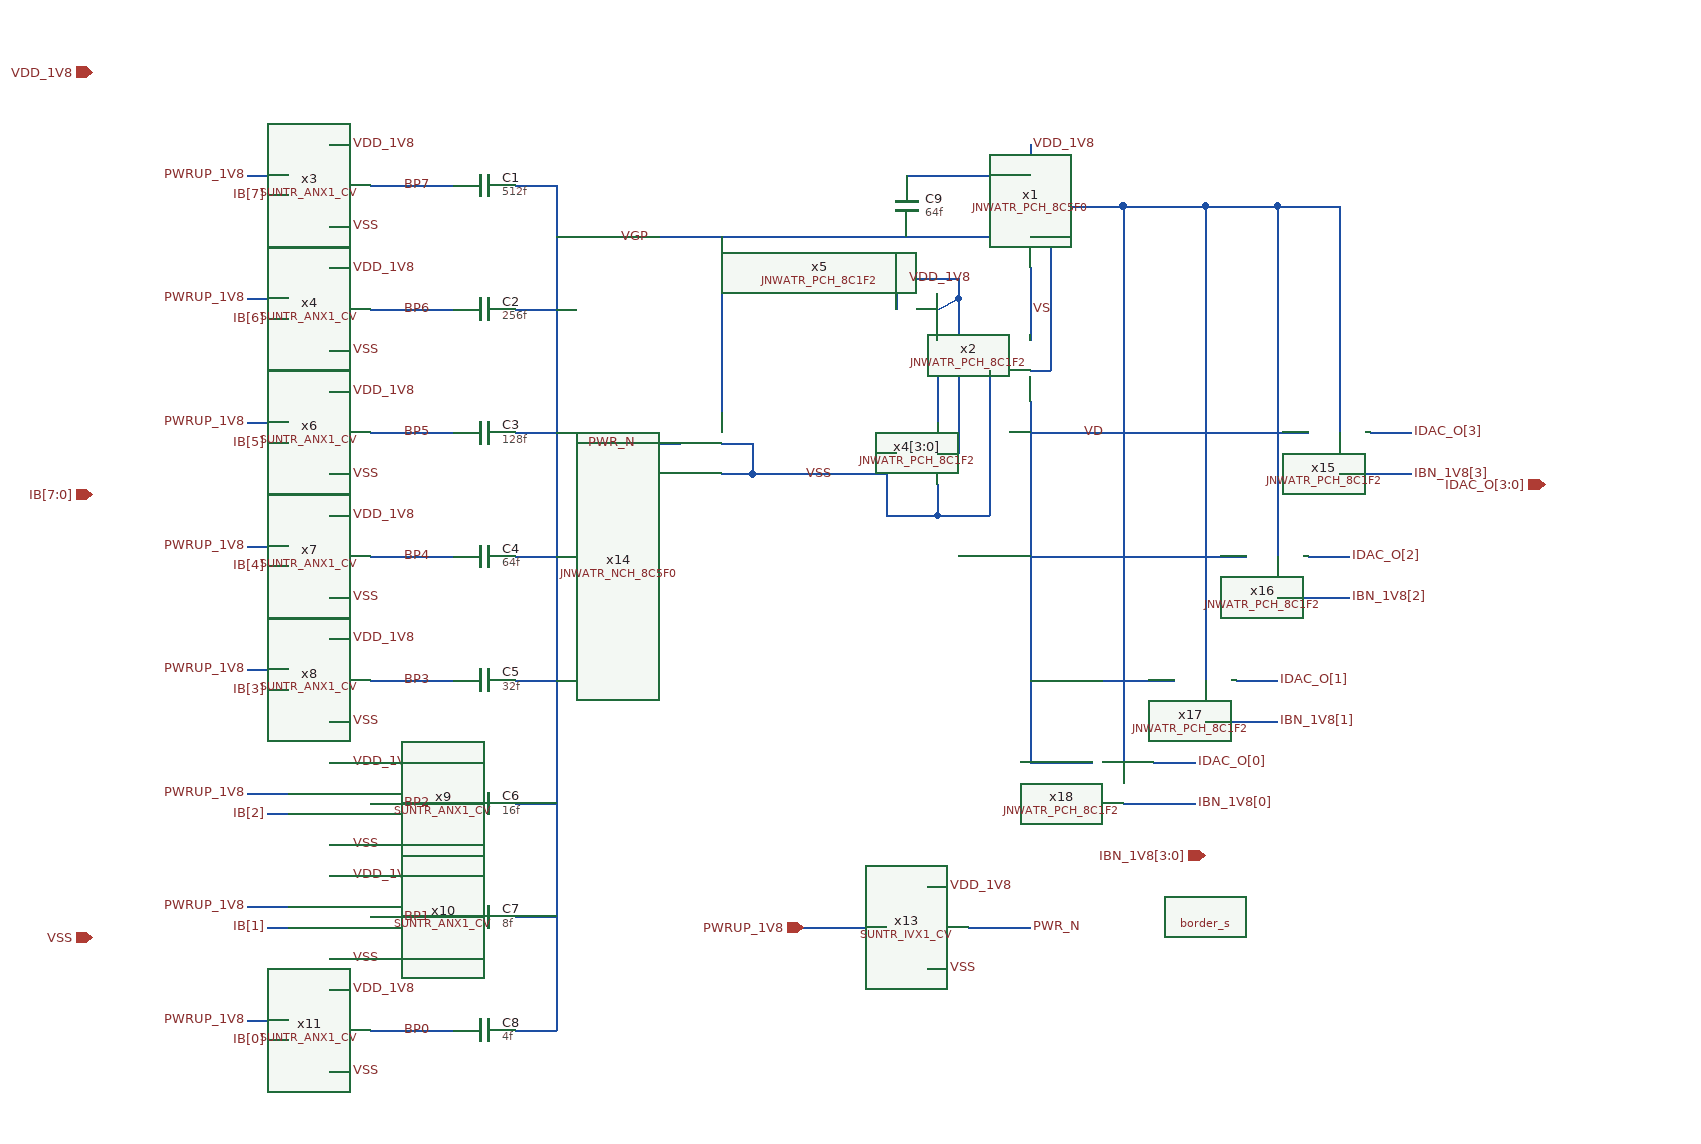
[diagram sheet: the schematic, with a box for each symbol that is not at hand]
v {xschem version=3.4.5 file_version=1.2
}
G {}
K {}
V {}
S {}
E {}
N 1080 -800 1080 -730 {
lab=VS}
N 1080 -700 1100 -700 {
lab=VDD_1V8}
N 1100 -830 1100 -700 {
lab=VDD_1V8}
N 1080 -830 1100 -830 {
lab=VDD_1V8}
N 1100 -860 1100 -830 {
lab=VDD_1V8}
N 1080 -860 1100 -860 {
lab=VDD_1V8}
N 1080 -920 1080 -860 {
lab=VDD_1V8}
N 990 -700 990 -650 {
lab=#net1}
N 990 -730 990 -700 {
lab=#net1}
N 990 -760 1010 -770 {
lab=VDD_1V8}
N 1010 -790 1010 -770 {
lab=VDD_1V8}
N 990 -790 1010 -790 {
lab=VDD_1V8}
N 950 -790 950 -760 {
lab=VDD_1V8}
N 950 -790 990 -790 {
lab=VDD_1V8}
N 990 -620 1010 -620 {
lab=VDD_1V8}
N 1010 -770 1010 -620 {
lab=VDD_1V8}
N 990 -590 990 -560 {
lab=VSS}
N 940 -560 990 -560 {
lab=VSS}
N 940 -620 940 -560 {
lab=VSS}
N 940 -620 950 -620 {
lab=VSS}
N 710 -830 1040 -830 {
lab=VGP}
N 400 -920 420 -920 {
lab=VDD_1V8}
N 400 -840 420 -840 {
lab=VSS}
N 340 -870 360 -870 {
lab=IB[7]}
N 400 -800 420 -800 {
lab=VDD_1V8}
N 400 -720 420 -720 {
lab=VSS}
N 340 -750 360 -750 {
lab=IB[6]}
N 400 -680 420 -680 {
lab=VDD_1V8}
N 400 -600 420 -600 {
lab=VSS}
N 340 -630 360 -630 {
lab=IB[5]}
N 400 -560 420 -560 {
lab=VDD_1V8}
N 400 -480 420 -480 {
lab=VSS}
N 340 -510 360 -510 {
lab=IB[4]}
N 400 -440 420 -440 {
lab=VDD_1V8}
N 400 -360 420 -360 {
lab=VSS}
N 340 -390 360 -390 {
lab=IB[3]}
N 400 -240 420 -240 {
lab=VSS}
N 340 -270 360 -270 {
lab=IB[2]}
N 400 -210 420 -210 {
lab=VDD_1V8}
N 400 -130 420 -130 {
lab=VSS}
N 340 -160 360 -160 {
lab=IB[1]}
N 400 -100 420 -100 {
lab=VDD_1V8}
N 400 -20 420 -20 {
lab=VSS}
N 340 -50 360 -50 {
lab=IB[0]}
N 440 -880 520 -880 {
lab=BP7}
N 580 -880 620 -880 {
lab=VGP}
N 440 -760 520 -760 {
lab=BP6}
N 580 -760 620 -760 {
lab=VGP}
N 440 -640 520 -640 {
lab=BP5}
N 580 -640 620 -640 {
lab=VGP}
N 440 -520 520 -520 {
lab=BP4}
N 580 -520 620 -520 {
lab=VGP}
N 440 -400 520 -400 {
lab=BP3}
N 580 -400 620 -400 {
lab=VGP}
N 440 -280 520 -280 {
lab=BP2}
N 580 -280 620 -280 {
lab=VGP}
N 440 -170 520 -170 {
lab=BP1}
N 580 -170 620 -170 {
lab=VGP}
N 440 -60 520 -60 {
lab=BP0}
N 580 -60 620 -60 {
lab=VGP}
N 620 -880 620 -60 {
lab=VGP}
N 620 -830 710 -830 {
lab=VGP}
N 1080 -670 1080 -490 {
lab=VD}
N 980 -200 1000 -200 {
lab=VDD_1V8}
N 980 -120 1000 -120 {
lab=VSS}
N 920 -160 940 -160 {
lab=PWRUP_1V8}
N 860 -160 920 -160 {
lab=PWRUP_1V8}
N 1020 -160 1080 -160 {
lab=PWR_N}
N 780 -830 780 -660 {
lab=VGP}
N 780 -630 810 -630 {
lab=VSS}
N 810 -630 810 -600 {
lab=VSS}
N 780 -600 810 -600 {
lab=VSS}
N 810 -600 940 -600 {
lab=VSS}
N 700 -630 740 -630 {
lab=PWR_N}
N 1170 -860 1170 -320 {
lab=VDD_1V8}
N 1100 -860 1170 -860 {
lab=VDD_1V8}
N 1250 -860 1250 -400 {
lab=VDD_1V8}
N 1170 -860 1250 -860 {
lab=VDD_1V8}
N 1250 -860 1320 -860 {
lab=VDD_1V8}
N 1380 -860 1380 -640 {
lab=VDD_1V8}
N 1320 -860 1380 -860 {
lab=VDD_1V8}
N 1080 -640 1350 -640 {
lab=VD}
N 1080 -490 1080 -320 {
lab=VD}
N 1080 -320 1140 -320 {
lab=VD}
N 1080 -400 1220 -400 {
lab=VD}
N 1080 -520 1290 -520 {
lab=VD}
N 1320 -860 1320 -520 {
lab=VDD_1V8}
N 1410 -640 1450 -640 {
lab=IDAC_O[3]}
N 1350 -520 1390 -520 {
lab=IDAC_O[2]}
N 1280 -400 1320 -400 {
lab=IDAC_O[1]}
N 1200 -320 1240 -320 {
lab=IDAC_O[0]}
N 1170 -280 1240 -280 {
lab=IBN_1V8[0]}
N 1250 -360 1320 -360 {
lab=IBN_1V8[1]}
N 1320 -480 1390 -480 {
lab=IBN_1V8[2]}
N 1380 -600 1450 -600 {
lab=IBN_1V8[3]}
N 400 -320 420 -320 {
lab=VDD_1V8}
N 320 -890 360 -890 {
lab=PWRUP_1V8}
N 320 -770 360 -770 {
lab=PWRUP_1V8}
N 320 -650 360 -650 {
lab=PWRUP_1V8}
N 320 -530 360 -530 {
lab=PWRUP_1V8}
N 320 -410 360 -410 {
lab=PWRUP_1V8}
N 320 -290 360 -290 {
lab=PWRUP_1V8}
N 320 -180 360 -180 {
lab=PWRUP_1V8}
N 320 -70 360 -70 {
lab=PWRUP_1V8}
N 1040 -700 1040 -560 {
lab=VSS}
N 990 -560 1040 -560 {
lab=VSS}
N 960 -890 1080 -890 {
lab=VDD_1V8}
C {devices/ipin.sym} 170 -990 0 0 {name=p1 lab=VDD_1V8}
C {devices/ipin.sym} 170 -150 0 0 {name=p2 lab=VSS}
C {devices/ipin.sym} 860 -160 0 0 {name=p3 lab=PWRUP_1V8}
C {JNW_ATR_SKY130NM/JNWATR_PCH_8C5F0.sym} 1040 -830 0 0 {name=x1 }
C {JNW_ATR_SKY130NM/JNWATR_PCH_8C1F2.sym} 1040 -700 0 0 {name=x2 }
C {JNW_ATR_SKY130NM/JNWATR_PCH_8C1F2.sym} 950 -620 0 0 {name=x4[3:0]}
C {JNW_ATR_SKY130NM/JNWATR_PCH_8C1F2.sym} 950 -760 0 0 {name=x5 }
C {devices/lab_wire.sym} 420 -920 0 1 {name=p4 sig_type=std_logic lab=VDD_1V8}
C {devices/lab_wire.sym} 420 -840 0 1 {name=p5 sig_type=std_logic lab=VSS}
C {devices/lab_wire.sym} 340 -870 0 0 {name=p6 sig_type=std_logic lab=IB[7]}
C {devices/lab_wire.sym} 420 -800 0 1 {name=p7 sig_type=std_logic lab=VDD_1V8}
C {devices/lab_wire.sym} 420 -720 0 1 {name=p8 sig_type=std_logic lab=VSS}
C {devices/lab_wire.sym} 340 -750 0 0 {name=p9 sig_type=std_logic lab=IB[6]}
C {devices/lab_wire.sym} 420 -680 0 1 {name=p10 sig_type=std_logic lab=VDD_1V8}
C {devices/lab_wire.sym} 420 -600 0 1 {name=p11 sig_type=std_logic lab=VSS}
C {devices/lab_wire.sym} 340 -630 0 0 {name=p12 sig_type=std_logic lab=IB[5]}
C {devices/lab_wire.sym} 420 -560 0 1 {name=p13 sig_type=std_logic lab=VDD_1V8}
C {devices/lab_wire.sym} 420 -480 0 1 {name=p14 sig_type=std_logic lab=VSS}
C {devices/lab_wire.sym} 340 -510 0 0 {name=p15 sig_type=std_logic lab=IB[4]}
C {devices/lab_wire.sym} 420 -440 0 1 {name=p16 sig_type=std_logic lab=VDD_1V8}
C {devices/lab_wire.sym} 420 -360 0 1 {name=p17 sig_type=std_logic lab=VSS}
C {devices/lab_wire.sym} 340 -390 0 0 {name=p18 sig_type=std_logic lab=IB[3]}
C {devices/lab_wire.sym} 420 -320 0 1 {name=p19 sig_type=std_logic lab=VDD_1V8}
C {devices/lab_wire.sym} 420 -240 0 1 {name=p20 sig_type=std_logic lab=VSS}
C {devices/lab_wire.sym} 340 -270 0 0 {name=p21 sig_type=std_logic lab=IB[2]}
C {devices/lab_wire.sym} 420 -210 0 1 {name=p22 sig_type=std_logic lab=VDD_1V8}
C {devices/lab_wire.sym} 420 -130 0 1 {name=p23 sig_type=std_logic lab=VSS}
C {devices/lab_wire.sym} 340 -160 0 0 {name=p24 sig_type=std_logic lab=IB[1]}
C {devices/lab_wire.sym} 420 -100 0 1 {name=p25 sig_type=std_logic lab=VDD_1V8}
C {devices/lab_wire.sym} 420 -20 0 1 {name=p26 sig_type=std_logic lab=VSS}
C {devices/lab_wire.sym} 340 -50 0 0 {name=p27 sig_type=std_logic lab=IB[0]}
C {devices/capa.sym} 550 -880 1 0 {name=C1
m=1
value=512f
footprint=1206
device="ceramic capacitor"}
C {devices/capa.sym} 550 -760 1 0 {name=C2
m=1
value=256f
footprint=1206
device="ceramic capacitor"}
C {devices/capa.sym} 550 -640 1 0 {name=C3
m=1
value=128f
footprint=1206
device="ceramic capacitor"}
C {devices/capa.sym} 550 -520 1 0 {name=C4
m=1
value=64f
footprint=1206
device="ceramic capacitor"}
C {devices/capa.sym} 550 -400 1 0 {name=C5
m=1
value=32f
footprint=1206
device="ceramic capacitor"}
C {devices/capa.sym} 550 -280 1 0 {name=C6
m=1
value=16f
footprint=1206
device="ceramic capacitor"}
C {devices/capa.sym} 550 -170 1 0 {name=C7
m=1
value=8f
footprint=1206
device="ceramic capacitor"}
C {devices/capa.sym} 550 -60 1 0 {name=C8
m=1
value=4f
footprint=1206
device="ceramic capacitor"}
C {devices/lab_wire.sym} 1080 -920 0 1 {name=p28 sig_type=std_logic lab=VDD_1V8}
C {SUN_TR_SKY130NM/SUNTR_IVX1_CV.sym} 940 -160 0 0 {name=x13 }
C {devices/lab_wire.sym} 1000 -200 0 1 {name=p29 sig_type=std_logic lab=VDD_1V8}
C {devices/lab_wire.sym} 1000 -120 0 1 {name=p30 sig_type=std_logic lab=VSS}
C {JNW_ATR_SKY130NM/JNWATR_NCH_8C5F0.sym} 740 -630 0 0 {name=x14 }
C {devices/lab_wire.sym} 860 -600 0 1 {name=p31 sig_type=std_logic lab=VSS}
C {devices/lab_wire.sym} 960 -790 0 1 {name=p32 sig_type=std_logic lab=VDD_1V8}
C {devices/lab_wire.sym} 1080 -160 0 1 {name=p33 sig_type=std_logic lab=PWR_N}
C {devices/lab_wire.sym} 700 -630 0 0 {name=p34 sig_type=std_logic lab=PWR_N}
C {devices/iopin.sym} 1580 -590 0 0 {name=p35 lab=IDAC_O[3:0]}
C {JNW_ATR_SKY130NM/JNWATR_PCH_8C1F2.sym} 1380 -600 3 0 {name=x15 }
C {JNW_ATR_SKY130NM/JNWATR_PCH_8C1F2.sym} 1320 -480 3 0 {name=x16 }
C {JNW_ATR_SKY130NM/JNWATR_PCH_8C1F2.sym} 1250 -360 3 0 {name=x17 }
C {JNW_ATR_SKY130NM/JNWATR_PCH_8C1F2.sym} 1170 -280 3 0 {name=x18 }
C {devices/lab_wire.sym} 1240 -320 0 1 {name=p36 sig_type=std_logic lab=IDAC_O[0]}
C {devices/lab_wire.sym} 1320 -400 0 1 {name=p37 sig_type=std_logic lab=IDAC_O[1]}
C {devices/lab_wire.sym} 1390 -520 0 1 {name=p38 sig_type=std_logic lab=IDAC_O[2]}
C {devices/lab_wire.sym} 1450 -640 0 1 {name=p39 sig_type=std_logic lab=IDAC_O[3]}
C {devices/lab_wire.sym} 1240 -280 0 1 {name=p40 sig_type=std_logic lab=IBN_1V8[0]}
C {devices/lab_wire.sym} 1320 -360 0 1 {name=p41 sig_type=std_logic lab=IBN_1V8[1]}
C {devices/lab_wire.sym} 1390 -480 0 1 {name=p42 sig_type=std_logic lab=IBN_1V8[2]}
C {devices/lab_wire.sym} 1450 -600 0 1 {name=p43 sig_type=std_logic lab=IBN_1V8[3]}
C {devices/ipin.sym} 170 -580 0 0 {name=p44 lab=IB[7:0]}
C {devices/ipin.sym} 1250 -230 0 0 {name=p45 lab=IBN_1V8[3:0]}
C {devices/lab_wire.sym} 1080 -760 0 1 {name=p47 sig_type=std_logic lab=VS}
C {devices/lab_wire.sym} 1130 -640 0 1 {name=p48 sig_type=std_logic lab=VD}
C {devices/lab_wire.sym} 680 -830 0 1 {name=p49 sig_type=std_logic lab=VGP}
C {SUN_TR_SKY130NM/SUNTR_ANX1_CV.sym} 360 -870 0 0 {name=x3 }
C {SUN_TR_SKY130NM/SUNTR_ANX1_CV.sym} 360 -750 0 0 {name=x4 }
C {SUN_TR_SKY130NM/SUNTR_ANX1_CV.sym} 360 -630 0 0 {name=x6 }
C {SUN_TR_SKY130NM/SUNTR_ANX1_CV.sym} 360 -510 0 0 {name=x7 }
C {SUN_TR_SKY130NM/SUNTR_ANX1_CV.sym} 360 -390 0 0 {name=x8 }
C {SUN_TR_SKY130NM/SUNTR_ANX1_CV.sym} 360 -270 0 0 {name=x9 }
C {SUN_TR_SKY130NM/SUNTR_ANX1_CV.sym} 360 -160 0 0 {name=x10 }
C {SUN_TR_SKY130NM/SUNTR_ANX1_CV.sym} 360 -50 0 0 {name=x11 }
C {devices/lab_wire.sym} 320 -890 0 0 {name=p50 sig_type=std_logic lab=PWRUP_1V8}
C {devices/lab_wire.sym} 320 -770 0 0 {name=p51 sig_type=std_logic lab=PWRUP_1V8}
C {devices/lab_wire.sym} 320 -650 0 0 {name=p52 sig_type=std_logic lab=PWRUP_1V8}
C {devices/lab_wire.sym} 320 -530 0 0 {name=p53 sig_type=std_logic lab=PWRUP_1V8}
C {devices/lab_wire.sym} 320 -410 0 0 {name=p54 sig_type=std_logic lab=PWRUP_1V8}
C {devices/lab_wire.sym} 320 -290 0 0 {name=p55 sig_type=std_logic lab=PWRUP_1V8}
C {devices/lab_wire.sym} 320 -180 0 0 {name=p56 sig_type=std_logic lab=PWRUP_1V8}
C {devices/lab_wire.sym} 320 -70 0 0 {name=p57 sig_type=std_logic lab=PWRUP_1V8}
C {cborder/border_s.sym} 1250 -170 0 0 {
user="wulff"
company="wulff"}
C {devices/lab_wire.sym} 500 -880 0 0 {name=p58 sig_type=std_logic lab=BP7
}
C {devices/lab_wire.sym} 500 -760 0 0 {name=p59 sig_type=std_logic lab=BP6
}
C {devices/lab_wire.sym} 500 -640 0 0 {name=p60 sig_type=std_logic lab=BP5
}
C {devices/lab_wire.sym} 500 -520 0 0 {name=p61 sig_type=std_logic lab=BP4
}
C {devices/lab_wire.sym} 500 -400 0 0 {name=p62 sig_type=std_logic lab=BP3
}
C {devices/lab_wire.sym} 500 -280 0 0 {name=p63 sig_type=std_logic lab=BP2
}
C {devices/lab_wire.sym} 500 -170 0 0 {name=p64 sig_type=std_logic lab=BP1
}
C {devices/lab_wire.sym} 500 -60 0 0 {name=p65 sig_type=std_logic lab=BP0
}
C {devices/capa.sym} 960 -860 2 0 {name=C9
m=1
value=64f
footprint=1206
device="ceramic capacitor"}
